One B-rep face of a CAD part: STEP entity #42753.
In plain terms, the planar face has unit normal (0, 1, 0).
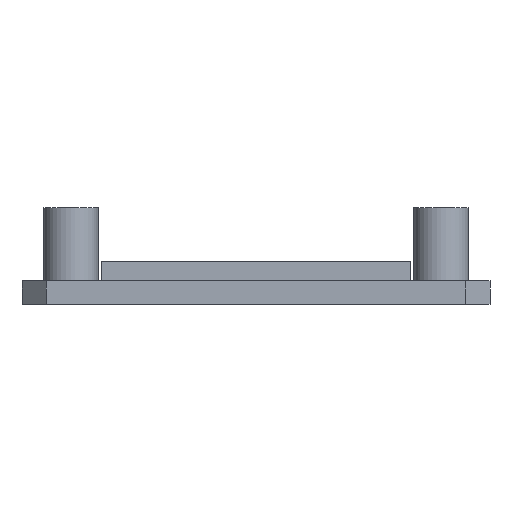
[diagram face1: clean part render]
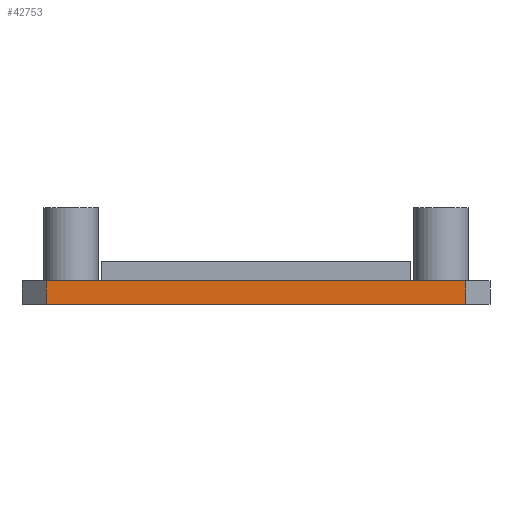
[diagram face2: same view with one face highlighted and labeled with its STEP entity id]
Its self-contained STEP definition (entity closure, numbers rounded to 3 decimals):
#90 = PLANE('',#91);
#91 = AXIS2_PLACEMENT_3D('',#92,#93,#94);
#92 = CARTESIAN_POINT('',(0.,0.,30.4)
  );
#93 = DIRECTION('',(0.,0.,1.));
#94 = DIRECTION('',(1.,0.,-0.));
#144 = PLANE('',#145);
#145 = AXIS2_PLACEMENT_3D('',#146,#147,#148);
#146 = CARTESIAN_POINT('',(0.,0.,28.)
  );
#147 = DIRECTION('',(0.,0.,1.));
#148 = DIRECTION('',(1.,0.,-0.));
#212 = VERTEX_POINT('',#213);
#213 = CARTESIAN_POINT('',(21.5,81.,30.4));
#227 = PLANE('',#228);
#228 = AXIS2_PLACEMENT_3D('',#229,#230,#231);
#229 = CARTESIAN_POINT('',(24.,78.5,28.));
#230 = DIRECTION('',(-0.707,-0.707,0.));
#231 = DIRECTION('',(-0.707,0.707,0.));
#239 = EDGE_CURVE('',#212,#240,#242,.T.);
#240 = VERTEX_POINT('',#241);
#241 = CARTESIAN_POINT('',(-21.5,81.,30.4));
#242 = SURFACE_CURVE('',#243,(#247,#254),.PCURVE_S1.);
#243 = LINE('',#244,#245);
#244 = CARTESIAN_POINT('',(21.5,81.,30.4));
#245 = VECTOR('',#246,1.);
#246 = DIRECTION('',(-1.,0.,0.));
#247 = PCURVE('',#90,#248);
#248 = DEFINITIONAL_REPRESENTATION('',(#249),#253);
#249 = LINE('',#250,#251);
#250 = CARTESIAN_POINT('',(21.5,81.));
#251 = VECTOR('',#252,1.);
#252 = DIRECTION('',(-1.,0.));
#253 = ( GEOMETRIC_REPRESENTATION_CONTEXT(2) 
PARAMETRIC_REPRESENTATION_CONTEXT() REPRESENTATION_CONTEXT('2D SPACE',''
  ) );
#254 = PCURVE('',#255,#260);
#255 = PLANE('',#256);
#256 = AXIS2_PLACEMENT_3D('',#257,#258,#259);
#257 = CARTESIAN_POINT('',(21.5,81.,28.));
#258 = DIRECTION('',(0.,-1.,0.));
#259 = DIRECTION('',(-1.,0.,0.));
#260 = DEFINITIONAL_REPRESENTATION('',(#261),#265);
#261 = LINE('',#262,#263);
#262 = CARTESIAN_POINT('',(0.,-2.4));
#263 = VECTOR('',#264,1.);
#264 = DIRECTION('',(1.,0.));
#265 = ( GEOMETRIC_REPRESENTATION_CONTEXT(2) 
PARAMETRIC_REPRESENTATION_CONTEXT() REPRESENTATION_CONTEXT('2D SPACE',''
  ) );
#283 = PLANE('',#284);
#284 = AXIS2_PLACEMENT_3D('',#285,#286,#287);
#285 = CARTESIAN_POINT('',(-21.5,81.,28.));
#286 = DIRECTION('',(0.707,-0.707,0.));
#287 = DIRECTION('',(-0.707,-0.707,0.));
#42753 = ADVANCED_FACE('',(#42754),#255,.F.);
#42754 = FACE_BOUND('',#42755,.F.);
#42755 = EDGE_LOOP('',(#42756,#42779,#42780,#42803));
#42756 = ORIENTED_EDGE('',*,*,#42757,.T.);
#42757 = EDGE_CURVE('',#42758,#212,#42760,.T.);
#42758 = VERTEX_POINT('',#42759);
#42759 = CARTESIAN_POINT('',(21.5,81.,28.));
#42760 = SURFACE_CURVE('',#42761,(#42765,#42772),.PCURVE_S1.);
#42761 = LINE('',#42762,#42763);
#42762 = CARTESIAN_POINT('',(21.5,81.,28.));
#42763 = VECTOR('',#42764,1.);
#42764 = DIRECTION('',(0.,0.,1.));
#42765 = PCURVE('',#255,#42766);
#42766 = DEFINITIONAL_REPRESENTATION('',(#42767),#42771);
#42767 = LINE('',#42768,#42769);
#42768 = CARTESIAN_POINT('',(0.,-0.));
#42769 = VECTOR('',#42770,1.);
#42770 = DIRECTION('',(0.,-1.));
#42771 = ( GEOMETRIC_REPRESENTATION_CONTEXT(2) 
PARAMETRIC_REPRESENTATION_CONTEXT() REPRESENTATION_CONTEXT('2D SPACE',''
  ) );
#42772 = PCURVE('',#227,#42773);
#42773 = DEFINITIONAL_REPRESENTATION('',(#42774),#42778);
#42774 = LINE('',#42775,#42776);
#42775 = CARTESIAN_POINT('',(3.536,0.));
#42776 = VECTOR('',#42777,1.);
#42777 = DIRECTION('',(0.,-1.));
#42778 = ( GEOMETRIC_REPRESENTATION_CONTEXT(2) 
PARAMETRIC_REPRESENTATION_CONTEXT() REPRESENTATION_CONTEXT('2D SPACE',''
  ) );
#42779 = ORIENTED_EDGE('',*,*,#239,.T.);
#42780 = ORIENTED_EDGE('',*,*,#42781,.F.);
#42781 = EDGE_CURVE('',#42782,#240,#42784,.T.);
#42782 = VERTEX_POINT('',#42783);
#42783 = CARTESIAN_POINT('',(-21.5,81.,28.));
#42784 = SURFACE_CURVE('',#42785,(#42789,#42796),.PCURVE_S1.);
#42785 = LINE('',#42786,#42787);
#42786 = CARTESIAN_POINT('',(-21.5,81.,28.));
#42787 = VECTOR('',#42788,1.);
#42788 = DIRECTION('',(0.,0.,1.));
#42789 = PCURVE('',#255,#42790);
#42790 = DEFINITIONAL_REPRESENTATION('',(#42791),#42795);
#42791 = LINE('',#42792,#42793);
#42792 = CARTESIAN_POINT('',(43.,0.));
#42793 = VECTOR('',#42794,1.);
#42794 = DIRECTION('',(0.,-1.));
#42795 = ( GEOMETRIC_REPRESENTATION_CONTEXT(2) 
PARAMETRIC_REPRESENTATION_CONTEXT() REPRESENTATION_CONTEXT('2D SPACE',''
  ) );
#42796 = PCURVE('',#283,#42797);
#42797 = DEFINITIONAL_REPRESENTATION('',(#42798),#42802);
#42798 = LINE('',#42799,#42800);
#42799 = CARTESIAN_POINT('',(0.,0.));
#42800 = VECTOR('',#42801,1.);
#42801 = DIRECTION('',(0.,-1.));
#42802 = ( GEOMETRIC_REPRESENTATION_CONTEXT(2) 
PARAMETRIC_REPRESENTATION_CONTEXT() REPRESENTATION_CONTEXT('2D SPACE',''
  ) );
#42803 = ORIENTED_EDGE('',*,*,#42804,.F.);
#42804 = EDGE_CURVE('',#42758,#42782,#42805,.T.);
#42805 = SURFACE_CURVE('',#42806,(#42810,#42817),.PCURVE_S1.);
#42806 = LINE('',#42807,#42808);
#42807 = CARTESIAN_POINT('',(21.5,81.,28.));
#42808 = VECTOR('',#42809,1.);
#42809 = DIRECTION('',(-1.,0.,0.));
#42810 = PCURVE('',#255,#42811);
#42811 = DEFINITIONAL_REPRESENTATION('',(#42812),#42816);
#42812 = LINE('',#42813,#42814);
#42813 = CARTESIAN_POINT('',(0.,-0.));
#42814 = VECTOR('',#42815,1.);
#42815 = DIRECTION('',(1.,0.));
#42816 = ( GEOMETRIC_REPRESENTATION_CONTEXT(2) 
PARAMETRIC_REPRESENTATION_CONTEXT() REPRESENTATION_CONTEXT('2D SPACE',''
  ) );
#42817 = PCURVE('',#144,#42818);
#42818 = DEFINITIONAL_REPRESENTATION('',(#42819),#42823);
#42819 = LINE('',#42820,#42821);
#42820 = CARTESIAN_POINT('',(21.5,81.));
#42821 = VECTOR('',#42822,1.);
#42822 = DIRECTION('',(-1.,0.));
#42823 = ( GEOMETRIC_REPRESENTATION_CONTEXT(2) 
PARAMETRIC_REPRESENTATION_CONTEXT() REPRESENTATION_CONTEXT('2D SPACE',''
  ) );
